VERSION 5.7 ;
  NOWIREEXTENSIONATPIN ON ;
  DIVIDERCHAR "/" ;
  BUSBITCHARS "[]" ;
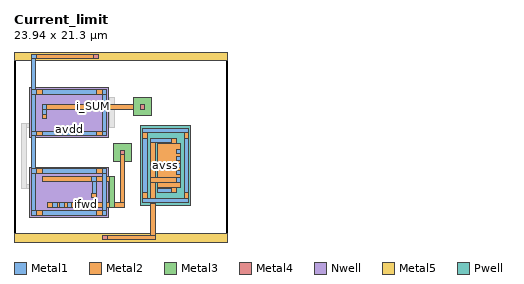
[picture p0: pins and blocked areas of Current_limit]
MACRO Current_limit
  CLASS BLOCK ;
  FOREIGN Current_limit ;
  ORIGIN 0.000 0.000 ;
  SIZE 23.940 BY 21.300 ;
  PIN i_SUM
    ANTENNADIFFAREA 0.300000 ;
    PORT
      LAYER Metal1 ;
        RECT 3.170 14.895 3.670 15.395 ;
        RECT 3.190 14.345 3.650 14.895 ;
        RECT 3.170 13.845 3.670 14.345 ;
      LAYER Metal2 ;
        RECT 3.170 14.895 14.645 15.395 ;
        RECT 3.170 13.845 3.670 14.345 ;
      LAYER Metal3 ;
        RECT 13.395 14.145 15.395 16.145 ;
      LAYER Metal4 ;
        RECT 14.145 14.895 14.645 15.395 ;
    END
  END i_SUM
  PIN ifwd
    ANTENNAGATEAREA 2.500000 ;
    ANTENNADIFFAREA 0.300000 ;
    PORT
      LAYER Metal1 ;
        RECT 8.730 6.795 9.230 7.295 ;
        RECT 8.750 5.445 9.210 6.795 ;
        RECT 8.730 4.945 9.230 5.445 ;
        RECT 4.350 3.905 4.850 4.405 ;
        RECT 5.150 3.905 5.650 4.405 ;
        RECT 5.950 3.905 6.450 4.405 ;
        RECT 6.750 3.905 7.250 4.405 ;
        RECT 7.550 3.905 8.050 4.405 ;
      LAYER Metal2 ;
        RECT 3.170 6.795 11.230 7.295 ;
        RECT 8.730 4.945 9.230 5.445 ;
        RECT 11.895 4.405 12.395 10.295 ;
        RECT 3.700 3.905 12.395 4.405 ;
      LAYER Metal3 ;
        RECT 11.145 9.045 13.145 11.045 ;
        RECT 10.730 3.905 11.230 7.295 ;
      LAYER Metal4 ;
        RECT 11.895 9.795 12.395 10.295 ;
    END
  END ifwd
  PIN avdd
    USE POWER ;
    ANTENNADIFFAREA 18.172800 ;
    PORT
      LAYER Nwell ;
        RECT 1.770 11.700 10.630 17.300 ;
        RECT 1.770 2.800 10.630 8.400 ;
      LAYER Metal1 ;
        RECT 2.000 20.550 2.500 21.050 ;
        RECT 2.000 17.090 2.460 20.550 ;
        RECT 2.000 16.590 2.500 17.090 ;
        RECT 3.150 16.590 9.250 17.090 ;
        RECT 9.900 16.590 10.400 17.090 ;
        RECT 2.000 12.410 2.460 16.590 ;
        RECT 9.940 12.410 10.400 16.590 ;
        RECT 2.000 11.910 2.500 12.410 ;
        RECT 3.150 11.910 9.250 12.410 ;
        RECT 9.900 11.910 10.400 12.410 ;
        RECT 2.000 8.190 2.460 11.910 ;
        RECT 2.000 7.690 2.500 8.190 ;
        RECT 3.150 7.690 9.250 8.190 ;
        RECT 9.900 7.690 10.400 8.190 ;
        RECT 2.000 3.510 2.460 7.690 ;
        RECT 9.940 3.510 10.400 7.690 ;
        RECT 2.000 3.010 2.500 3.510 ;
        RECT 3.150 3.010 9.250 3.510 ;
        RECT 9.900 3.010 10.400 3.510 ;
      LAYER Metal2 ;
        RECT 2.000 20.550 9.420 21.050 ;
        RECT 2.000 16.590 10.400 17.090 ;
        RECT 2.000 11.910 10.400 12.410 ;
        RECT 2.000 7.690 10.400 8.190 ;
        RECT 2.000 3.010 10.400 3.510 ;
      LAYER Metal3 ;
        RECT 8.920 20.550 9.420 21.050 ;
      LAYER Metal4 ;
        RECT 8.920 20.550 9.420 21.050 ;
      LAYER Metal5 ;
        RECT 0.000 20.300 23.940 21.300 ;
    END
  END avdd
  PIN avss
    USE GROUND ;
    ANTENNAGATEAREA 2.500000 ;
    ANTENNADIFFAREA 9.686399 ;
    PORT
      LAYER Pwell ;
        RECT 14.210 4.145 19.810 13.005 ;
      LAYER Metal1 ;
        RECT 14.420 12.315 19.600 12.775 ;
        RECT 14.420 12.275 14.920 12.315 ;
        RECT 19.100 12.275 19.600 12.315 ;
        RECT 14.420 5.525 14.920 11.625 ;
        RECT 15.315 11.585 15.815 11.605 ;
        RECT 17.165 11.585 17.665 11.605 ;
        RECT 15.315 11.125 17.665 11.585 ;
        RECT 15.315 11.105 15.815 11.125 ;
        RECT 17.165 11.105 17.665 11.125 ;
        RECT 18.205 9.925 18.705 10.425 ;
        RECT 18.205 9.125 18.705 9.625 ;
        RECT 18.205 8.325 18.705 8.825 ;
        RECT 18.205 7.525 18.705 8.025 ;
        RECT 18.205 6.725 18.705 7.225 ;
        RECT 16.115 6.025 16.615 6.045 ;
        RECT 17.165 6.025 17.665 6.045 ;
        RECT 16.115 5.565 17.665 6.025 ;
        RECT 16.115 5.545 16.615 5.565 ;
        RECT 17.165 5.545 17.665 5.565 ;
        RECT 19.100 5.525 19.600 11.625 ;
        RECT 14.420 4.835 14.920 4.875 ;
        RECT 15.315 4.835 15.815 4.855 ;
        RECT 19.100 4.835 19.600 4.875 ;
        RECT 14.420 4.375 19.600 4.835 ;
        RECT 15.315 4.355 15.815 4.375 ;
      LAYER Metal2 ;
        RECT 14.420 4.375 14.920 12.775 ;
        RECT 15.315 7.225 15.815 11.605 ;
        RECT 16.115 11.075 18.205 11.605 ;
        RECT 16.115 7.225 18.705 11.075 ;
        RECT 15.315 6.725 18.705 7.225 ;
        RECT 15.315 0.750 15.815 6.725 ;
        RECT 16.115 6.075 18.705 6.725 ;
        RECT 16.115 5.545 18.205 6.075 ;
        RECT 19.100 4.375 19.600 12.775 ;
        RECT 9.950 0.250 15.815 0.750 ;
      LAYER Metal3 ;
        RECT 9.950 0.250 10.450 0.750 ;
      LAYER Metal4 ;
        RECT 9.950 0.250 10.450 0.750 ;
      LAYER Metal5 ;
        RECT 0.000 0.000 23.940 1.000 ;
    END
  END avss
  OBS
      LAYER Metal1 ;
        RECT 8.730 15.695 9.230 16.195 ;
        RECT 8.750 14.345 9.210 15.695 ;
        RECT 8.730 13.845 9.230 14.345 ;
        RECT 4.350 12.805 4.850 13.305 ;
        RECT 5.150 12.805 5.650 13.305 ;
        RECT 5.950 12.805 6.450 13.305 ;
        RECT 6.750 12.805 7.250 13.305 ;
        RECT 7.550 12.805 8.050 13.305 ;
        RECT 3.170 5.995 3.670 6.495 ;
        RECT 3.190 5.445 3.650 5.995 ;
        RECT 3.170 4.945 3.670 5.445 ;
      LAYER Metal2 ;
        RECT 3.170 15.695 11.230 16.195 ;
        RECT 8.730 13.845 9.230 14.345 ;
        RECT 0.870 12.805 11.230 13.305 ;
        RECT 0.870 5.995 9.230 6.495 ;
        RECT 3.170 4.945 3.670 5.445 ;
      LAYER Metal3 ;
        RECT 0.870 5.995 1.370 13.305 ;
        RECT 10.730 12.805 11.230 16.195 ;
  END
END Current_limit
END LIBRARY

